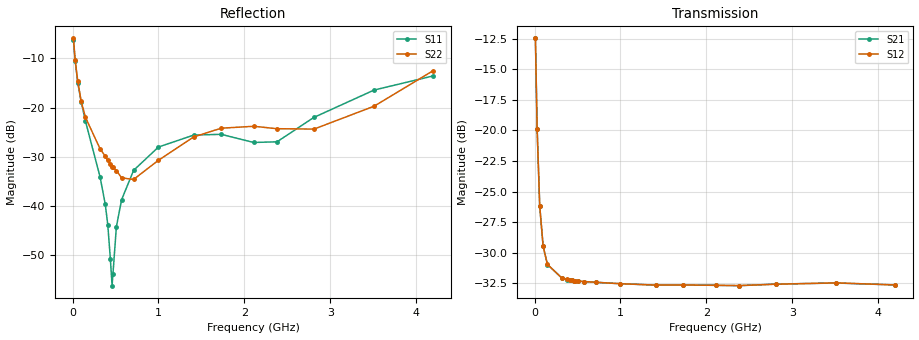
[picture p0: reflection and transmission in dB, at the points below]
! Integrated Device Technology
! Corporate Headquarters
! 6024 Silver Creek Valley Road
! San Jose, CA 95138  USA
! Phone:  1-408-284-8200
! Toll Free:  1-800-223-1366
! Webpage:  http://www.idt.com/
! Timing and RF Division
! 515 Groton Road, Suite 102
! Westford, MA 01886-6024
! Device:  F1950
! Description: 7-bit 0.25 dB Digital Step Attenuator
! Frequency:  150.0 -  4000.00 MHz
! Package:  4x4 mm Thin QFN Plastic Package: 24 pin
! Ports:  2 RF, 12 DC
!  Pin  1  = D0
!  Pin  2  = VDD
!  Pin  3  = Vmode
!  Pin  4  = GND
!  Pin  5  = RF1  =  Port 1
!  Pin  6  = GND
!  Pin  7  = GND
!  Pin  8  = GND
!  Pin  9  = GND
!  Pin 10  = GND
!  Pin 11  = GND
!  Pin 12  = GND
!  Pin 13  = GND
!  Pin 14  = RF2  =  Port 2
!  Pin 15  = GND
!  Pin 16  = LE
!  Pin 17  = CLK
!  Pin 18  = DATE
!  Pin 19  = D6
!  Pin 20  = D5
!  Pin 21  = D4
!  Pin 22  = D3
!  Pin 23  = D2
!  Pin 24  = D1
! State:  126
! Atten State:  31.50 dB
! Voltage:  +5.00 Volts
! Current:  Not Measured mA
! Data:  The device was measured on a the F195X evaluation board which has
!  individual transmission lines to the RF pins.  Data was collected
!  using a calibrated network analyzer.  The evaluation board was
!  de-embedded using a TRL calibration technique.
!  The reference plane is the edge of the package pin.
! Misc:  Board 2019
!  Action Tracker AT0250
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# GHz S dB R 50
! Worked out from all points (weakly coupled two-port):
!   420 points, 10 MHz to 4.2 GHz, reference 50 ohm
!   highest |S21| = -12.49 dB at 10 MHz (marker M1); lowest = -32.7 dB at 2.38 GHz (marker M2)
!   lowest |S11| = -56.2 dB at 460 MHz (marker M3), VSWR 1.00, Z = 49.9 - j0.0602 ohm
!   |S11| at or under -10 dB: 27.55 MHz to end of sweep
!   |S22| runs from -34.9 to -5.9 dB; largest |S21 - S12| = 7.2e-05
!   S11 on the Smith chart (normalised r, x): 10 MHz: 1.97, -1.24; 30 MHz: 1.27, -0.65; 60 MHz: 1.11, -0.37; 380 MHz: 1.01, -0.02; 4.2 GHz: 0.69, +0.17
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0.01  -6.20 -29.3  -12.49 -43.8  -12.48 -43.8  -5.93 -29.7
0.03  -10.48 -51.5  -19.89 -67.3  -19.89 -67.3  -10.24 -53.6
0.06  -14.92 -64.1  -26.17 -61.7  -26.17 -61.7  -14.61 -66.3
0.1  -18.80 -70.7  -29.47 -47.0  -29.47 -47.0  -18.72 -71.7
0.15  -22.76 -72.5  -30.95 -34.9  -30.94 -35.0  -21.99 -75.9
0.32  -34.08 -71.8  -32.07 -19.3  -32.07 -19.4  -28.36 -85.1
0.38  -39.58 -70.8  -32.18 -17.2  -32.17 -17.2  -29.86 -87.9
0.41  -43.80 -77.3  -32.21 -16.4  -32.21 -16.4  -30.73 -89.5
0.44  -50.77 -96.2  -32.25 -15.7  -32.25 -15.7  -31.55 -93.6
0.46  -56.17 -157.2  -32.27 -15.3  -32.27 -15.3  -31.96 -97.0
0.47  -53.76 165.7  -32.28 -15.1  -32.28 -15.1  -32.10 -98.6
0.51  -44.20 139.7  -32.31 -14.5  -32.30 -14.5  -32.78 -102.8
0.57  -38.75 134.1  -32.34 -13.8  -32.34 -13.9  -34.26 -113.6
0.71  -32.75 137.2  -32.40 -12.9  -32.40 -12.9  -34.59 -141.2
1  -28.00 147.0  -32.52 -12.6  -32.52 -12.6  -30.69 178.5
1.41  -25.58 162.0  -32.63 -13.2  -32.63 -13.2  -25.95 160.1
1.73  -25.42 167.1  -32.62 -13.9  -32.62 -13.9  -24.18 151.7
2.11  -27.08 156.1  -32.65 -15.9  -32.65 -15.9  -23.79 141.7
2.38  -26.94 128.8  -32.68 -16.7  -32.67 -16.7  -24.28 132.9
2.81  -21.98 104.1  -32.55 -19.0  -32.56 -19.1  -24.36 115.5
3.51  -16.43 116.6  -32.46 -22.5  -32.45 -22.6  -19.71 112.9
4.2  -13.55 145.1  -32.62 -23.2  -32.62 -23.3  -12.47 127.0
